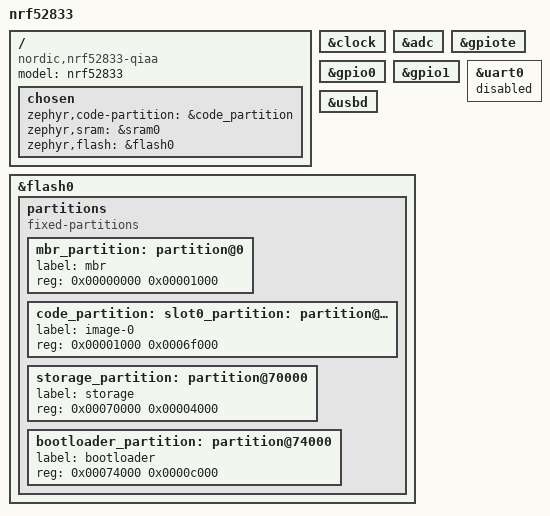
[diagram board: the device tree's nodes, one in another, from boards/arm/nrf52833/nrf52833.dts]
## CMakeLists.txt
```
cmake_minimum_required(VERSION 3.20.0)

set(NO_BUILD_TYPE_WARNING ON)
list(APPEND BOARD_ROOT ${CMAKE_CURRENT_SOURCE_DIR})

set(KBD_HEADER "${CMAKE_CURRENT_SOURCE_DIR}/keyboards/${KEYBOARD}/keyboard.h")

if(EXISTS ${KBD_HEADER})
  file(READ ${KBD_HEADER} _kbd_h)

  if(_kbd_h MATCHES "#define[ \t]+RGB[ \t]+true")
    string(REGEX MATCH "#define[ \t]+RGB_PORT[ \t]+([0-9]+)" _ "${_kbd_h}")
    set(RGB_PORT ${CMAKE_MATCH_1})
    string(REGEX MATCH "#define[ \t]+RGB_PIN[ \t]+([0-9]+)"  _ "${_kbd_h}")
    set(RGB_PIN  ${CMAKE_MATCH_1})
    string(REGEX MATCH "#define[ \t]+RGB_LEDS[ \t]+([0-9]+)" _ "${_kbd_h}")
    set(RGB_LEDS ${CMAKE_MATCH_1})

    if(RGB_PORT STREQUAL "" OR RGB_PIN STREQUAL "" OR RGB_LEDS STREQUAL "")
      message(FATAL_ERROR "RGB enabled for ${KEYBOARD} but RGB_PORT/RGB_PIN/RGB_LEDS not defined in keyboard.h")
    endif()

    message(STATUS "RGB enabled for ${KEYBOARD}: port=${RGB_PORT} pin=${RGB_PIN} leds=${RGB_LEDS}")
    list(APPEND EXTRA_CONF_FILE "boards/arm/common/rgb.conf")
    list(APPEND DTC_OVERLAY_FILE "boards/arm/common/rgb.overlay")
    list(APPEND DTS_EXTRA_CPPFLAGS
      "-DRGB_PORT=${RGB_PORT}"
      "-DRGB_PIN=${RGB_PIN}"
      "-DRGB_LEDS=${RGB_LEDS}")
  endif()

  if(_kbd_h MATCHES "#define[ \t]+LOGS[ \t]+true")
    list(APPEND EXTRA_CONF_FILE "boards/arm/common/logs.conf")
    list(APPEND DTC_OVERLAY_FILE "boards/arm/common/logs.overlay")
  endif()
endif()

list(APPEND DTC_OVERLAY_FILE "boards/arm/common/battery.overlay")

find_package(Zephyr REQUIRED HINTS $ENV{ZEPHYR_BASE})
project(keyboard-firmware)

if(NOT DEFINED KEYBOARD)
  message(FATAL_ERROR "KEYBOARD not defined. Example: -DKEYBOARD=miguelio/mk60v1")
endif()

target_include_directories(app PRIVATE src)
target_include_directories(app PRIVATE keyboards/${KEYBOARD})

target_sources(app PRIVATE
  keyboards/${KEYBOARD}/keyboard.c
  keyboards/${KEYBOARD}/keymap.c
  src/battery/battery.c
  src/main.c
)
```

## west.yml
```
manifest:
  remotes:
    - name: zephyrproject-rtos
      url-base: https://github.com/zephyrproject-rtos

  projects:
    - name: zephyr
      remote: zephyrproject-rtos
      revision: v3.6.0
      clone-depth: 1
      import:
        name-allowlist:
          - cmsis
          - hal_nordic
          - mbedtls
          - tinycrypt
          - segger

  self:
    path: app
```

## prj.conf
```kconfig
# General
CONFIG_LOG=y
CONFIG_PRINTK=y
CONFIG_REBOOT=y
CONFIG_MPU_STACK_GUARD=y

# Bluetooth
CONFIG_BT=y
CONFIG_BT_PERIPHERAL=y
CONFIG_BT_DEVICE_NAME="BMK Keyboard"
CONFIG_BT_DEVICE_APPEARANCE=961
CONFIG_BT_MAX_CONN=1
CONFIG_BT_MAX_PAIRED=1
CONFIG_BT_GATT_DYNAMIC_DB=y

# BLE Security - pairing support for HID
CONFIG_BT_SMP=y
CONFIG_BT_SMP_SC_ONLY=n
CONFIG_BT_SMP_SC_PAIR_ONLY=n
CONFIG_BT_SMP_ALLOW_UNAUTH_OVERWRITE=y

# BLE connection parameters for compatibility
CONFIG_BT_PERIPHERAL_PREF_MIN_INT=6
CONFIG_BT_PERIPHERAL_PREF_MAX_INT=9
CONFIG_BT_PERIPHERAL_PREF_LATENCY=150
CONFIG_BT_PERIPHERAL_PREF_TIMEOUT=400

# Security
CONFIG_BT_SMP=y
CONFIG_BT_ID_MAX=2
CONFIG_BT_KEYS_OVERWRITE_OLDEST=y

# Performance
CONFIG_BT_CTLR_TX_PWR_PLUS_8=y
CONFIG_BT_L2CAP_TX_BUF_COUNT=8

# Watchdog
CONFIG_WATCHDOG=y
CONFIG_WDT_DISABLE_AT_BOOT=y

# Device Information Service
CONFIG_BT_DIS=y
CONFIG_BT_DIS_PNP=y
CONFIG_BT_DIS_PNP_VID_SRC=2
CONFIG_BT_DIS_PNP_VID=0x1D50
CONFIG_BT_DIS_PNP_PID=0x615E
CONFIG_BT_DIS_PNP_VER=0x0001
CONFIG_BT_DIS_MODEL="BMK Keyboard"
CONFIG_BT_DIS_MANUF="BMK"

# Battery Service
CONFIG_BT_BAS=y
CONFIG_ADC=y

# Settings
CONFIG_SETTINGS=y
CONFIG_BT_SETTINGS=y
CONFIG_SETTINGS_DYNAMIC_HANDLERS=y

# USB HID
CONFIG_USB_DEVICE_STACK=y
CONFIG_USB_DEVICE_HID=y
CONFIG_USB_DEVICE_PRODUCT="BMK Keyboard"
CONFIG_USB_DEVICE_VID=0x1D50
CONFIG_USB_DEVICE_PID=0x615E
CONFIG_USB_DEVICE_INITIALIZE_AT_BOOT=y
```

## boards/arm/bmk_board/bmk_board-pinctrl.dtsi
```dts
/*
 * Copyright (c) 2025 Miguelio
 * SPDX-License-Identifier: MIT
 */

&pinctrl {
};
```

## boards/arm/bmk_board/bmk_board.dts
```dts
/*
 * Copyright (c) 2025 Miguelio
 * SPDX-License-Identifier: MIT
 *
 * Board: E73-2G4M08S1C (nRF52840)
 * - No external 32.768kHz crystal (uses internal RC)
 * - Powered via VDDH from USB (5V)
 */

/dts-v1/;
#include <nordic/nrf52840_qiaa.dtsi>

/ {
	model = "bmk_board";
	compatible = "bmk_board";

	chosen {
		zephyr,code-partition = &code_partition;
		zephyr,sram = &sram0;
		zephyr,flash = &flash0;
		zephyr,console = &uart0;
		zephyr,shell-uart = &uart0;
	};

};

&adc {
	status = "okay";
};

&gpiote {
	status = "okay";
};

&gpio0 {
	status = "okay";
};

&gpio1 {
	status = "okay";
};

&uart0 {
	status = "disabled";
};

zephyr_udc0: &usbd {
	status = "okay";
};

&flash0 {
	partitions {
		compatible = "fixed-partitions";
		#address-cells = <1>;
		#size-cells = <1>;

		sd_partition: partition@0 {
			reg = <0x00000000 0x00001000>;
		};

		code_partition: partition@1000 {
			reg = <0x00001000 0x000d3000>;
		};

		storage_partition: partition@d4000 {
			reg = <0x000d4000 0x00020000>;
		};

		boot_partition: partition@f4000 {
			reg = <0x000f4000 0x0000c000>;
		};
	};
};
```

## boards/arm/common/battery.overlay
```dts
/ {
    zephyr,user {
        io-channels = <&adc 0>;
    };
};

&adc {
    status = "okay";
    #address-cells = <1>;
    #size-cells = <0>;

    channel@0 {
        reg = <0>;
        zephyr,gain = "ADC_GAIN_1_2";
        zephyr,reference = "ADC_REF_INTERNAL";
        zephyr,acquisition-time = <ADC_ACQ_TIME(ADC_ACQ_TIME_MICROSECONDS, 20)>;
        zephyr,oversampling = <2>;
        zephyr,input-positive = <NRF_SAADC_VDDHDIV5>;
        zephyr,resolution = <12>;
    };
};
```

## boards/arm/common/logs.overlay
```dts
/ {
	chosen {
        zephyr,console = &cdc_acm_uart0;
		zephyr,shell-uart = &cdc_acm_uart0;
	};
};

zephyr_udc0: &usbd {
	status = "okay";

	cdc_acm_uart0: cdc_acm_uart0 {
		compatible = "zephyr,cdc-acm-uart";
	};
};
```

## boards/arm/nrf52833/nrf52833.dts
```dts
/*
 * Copyright (c) 2026 Miguelio
 * SPDX-License-Identifier: MIT
 *
 * Board: E73-2G4M08S1C (nRF52833)
 * - No external 32.768kHz crystal (uses internal RC)
 * - Powered via VDDH from USB (5V)
 */

/dts-v1/;
#include <nordic/nrf52833_qiaa.dtsi>

/ {
	model = "nrf52833";
	compatible = "nordic,nrf52833-qiaa";

	chosen {
		zephyr,code-partition = &code_partition;
		zephyr,sram = &sram0;
		zephyr,flash = &flash0;
	};
};

&clock {
	status = "okay";
};

&adc {
	status = "okay";
};

&gpiote {
	status = "okay";
};

&gpio0 {
	status = "okay";
};

&gpio1 {
	status = "okay";
};

&uart0 {
	status = "disabled";
};

zephyr_udc0: &usbd {
	status = "okay";
};

&flash0 {
    partitions {
        compatible = "fixed-partitions";
        #address-cells = <1>;
        #size-cells = <1>;

        mbr_partition: partition@0 {
            label = "mbr";
            reg = <0x00000000 0x00001000>;
        };

        code_partition: slot0_partition: partition@1000 {
            label = "image-0";
            reg = <0x00001000 0x0006f000>; /* Hasta la 0x70000 */
        };

        storage_partition: partition@70000 {
            label = "storage";
            reg = <0x00070000 0x00004000>; /* 16KB para datos */
        };

        bootloader_partition: partition@74000 {
            label = "bootloader";
            reg = <0x00074000 0x0000c000>; /* 48KB finales */
        };
    };
};
```

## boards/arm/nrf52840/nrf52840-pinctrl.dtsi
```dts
/*
 * Copyright (c) 2026 Miguelio
 * SPDX-License-Identifier: MIT
 */

&pinctrl {
};
```

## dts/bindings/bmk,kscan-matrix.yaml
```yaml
description: BMK keyboard scan matrix

compatible: "bmk,kscan-matrix"

properties:
  col-gpios:
    type: phandle-array
    required: true
    description: Column GPIO pins (active high output)

  row-gpios:
    type: phandle-array
    required: true
    description: Row GPIO pins (active high input with pull-down)
```

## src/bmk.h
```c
#ifndef BMK_H
#define BMK_H

#include <zephyr/types.h>
#include <stdint.h>
#include <stdbool.h>
#include <zephyr/kernel.h>
#include <zephyr/drivers/gpio.h>
#include <zephyr/bluetooth/bluetooth.h>
#include <zephyr/bluetooth/conn.h>
#include <zephyr/bluetooth/gatt.h>
#include <zephyr/bluetooth/uuid.h>
#include <zephyr/usb/usb_device.h>
#include <zephyr/usb/class/usb_hid.h>
#include <zephyr/pm/device.h>
#include <hal/nrf_power.h>
#include <zephyr/drivers/gpio.h>
#include <zephyr/device.h>
#include <zephyr/usb/class/usb_hid.h>
#include <zephyr/devicetree.h>
#include <zephyr/drivers/gpio.h>
#include <zephyr/logging/log.h>
#include <zephyr/drivers/led_strip.h>
#include <zephyr/bluetooth/services/bas.h>
#include <zephyr/settings/settings.h>
#include <zephyr/sys/reboot.h>
#include <hal/nrf_gpio.h>

#include "hid.h"

#define ENCODER_PINS 2

#define P0(pin) (0x0000 | (pin & 0xFF))
#define P1(pin) (0x0100 | (pin & 0xFF))

extern const uint16_t pin_cols[];
extern const uint16_t pin_rows[];
extern const uint16_t pin_encoders[ENCODER_PINS];
extern const uint16_t pin_power_ext;

#define GPIO0 DEVICE_DT_GET(DT_NODELABEL(gpio0))
#define GPIO1 DEVICE_DT_GET(DT_NODELABEL(gpio1))

#endif
```

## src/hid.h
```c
#pragma once

#include <zephyr/sys/util.h>

#include <zephyr/usb/usb_device.h>
#include <zephyr/usb/class/usb_hid.h>

#define K_KEYBOARD 0x0000
#define K_CONSUMER 0x1000
#define K_FN 0x2000
#define K_SPECIAL 0x3000
#define K_TAP_HOLD 0xE000

#define HID_KEY_LCTRL (K_KEYBOARD | 0xE0)
#define HID_KEY_LSHIFT (K_KEYBOARD | 0xE1)
#define HID_KEY_LALT (K_KEYBOARD | 0xE2)
#define HID_KEY_LGUI (K_KEYBOARD | 0xE3)
#define HID_KEY_RCTRL (K_KEYBOARD | 0xE4)
#define HID_KEY_RSHIFT (K_KEYBOARD | 0xE5)
#define HID_KEY_RALT (K_KEYBOARD | 0xE6)
#define HID_KEY_RGUI (K_KEYBOARD | 0xE7)

#define HID_KEY_NONE 0
#define HID_KEY_NUBS 0x64
#define HID_KEY_VOLUME_UP (K_CONSUMER | 0xE9)
#define HID_KEY_VOLUME_DOWN (K_CONSUMER | 0xEA)
#define HID_KEY_MUTE (K_CONSUMER | 0xE2)
#define HID_KEY_PLAY_PAUSE (K_CONSUMER | 0xCD)
#define HID_KEY_NEXT_TRACK (K_CONSUMER | 0xB5)
#define HID_KEY_PREV_TRACK (K_CONSUMER | 0xB6)
#define HID_KEY_STOP (K_CONSUMER | 0xB7)
#define HID_KEY_EJECT (K_CONSUMER | 0xB8)
#define HID_KEY_SLEEP (K_CONSUMER | 0x32)

#define HID_KEY_TRANS (K_SPECIAL | 0x01)

#define HID_KEY_POWER_ON (K_SPECIAL | 0x02)
#define HID_KEY_POWER_OFF (K_SPECIAL | 0x03)

#define HID_KEY_RGB_LIGHT (K_SPECIAL | 0x04)
#define HID_KEY_RGB_COLOR (K_SPECIAL | 0x05)
#define HID_KEY_RGB_SATURATION (K_SPECIAL | 0x06)
#define HID_KEY_RGB_ON (K_SPECIAL | 0x07)
#define HID_KEY_RGB_OFF (K_SPECIAL | 0x08)
#define HID_KEY_RGB_TOGGLE (K_SPECIAL | 0x09)

#define HID_BT_CLEAR (K_SPECIAL | 0x0A)
#define HID_DEEP_SLEEP (K_SPECIAL | 0x0B)
#define HID_RESET (K_SPECIAL | 0x0C)
#define HID_BOOT (K_SPECIAL | 0x0D)

#define BMK_HID_REPORT_ID_KEYBOARD 0x01
#define BMK_HID_REPORT_ID_CONSUMER 0x02
#define BMK_HID_REPORT_ID_LEDS 0x01

#define HID_USAGE_GD_KEYBOARD (0x06)
#define HID_USAGE_KEY (0x07)
#define HID_USAGE_LED (0x08)
#define HID_USAGE_CONSUMER (0x0C)
#define HID_USAGE_KEY_KEYBOARD_LEFTCONTROL (0xE0)
#define HID_USAGE_KEY_KEYBOARD_RIGHT_GUI (0xE7)
#define HID_USAGE_LED_NUM_LOCK (0x01)
#define HID_USAGE_LED_KANA (0x05)
#define HID_USAGE_CONSUMER_CONSUMER_CONTROL (0x01)

#define FN_MO(layer) (0x2100 | (layer & 0xFF))
#define FN_TO(layer) (0x2200 | (layer & 0xFF))
#define TH_LCTRL(key) (0xE000 | (key & 0xFF))
#define TH_LSHIFT(key) (0xE100 | (key & 0xFF))
#define TH_LALT(key) (0xE200 | (key & 0xFF))
#define TH_LGUI(key) (0xE300 | (key & 0xFF))
#define TH_RCTRL(key) (0xE400 | (key & 0xFF))
#define TH_RSHIFT(key) (0xE500 | (key & 0xFF))
#define TH_RALT(key) (0xE600 | (key & 0xFF))
#define TH_RGUI(key) (0xE700 | (key & 0xFF))

#define BMK_HID_MAIN_VAL_DATA (0x00 << 0)
#define BMK_HID_MAIN_VAL_VAR (0x01 << 1)
#define BMK_HID_MAIN_VAL_ABS (0x00 << 2)
#define BMK_HID_MAIN_VAL_CONST (0x01 << 0)
#define BMK_HID_MAIN_VAL_ARRAY (0x00 << 1)

static const uint8_t hid_report_map[] = {
    HID_USAGE_PAGE(HID_USAGE_GEN_DESKTOP),
    HID_USAGE(HID_USAGE_GD_KEYBOARD),
    HID_COLLECTION(HID_COLLECTION_APPLICATION),
    HID_REPORT_ID(BMK_HID_REPORT_ID_KEYBOARD),
    HID_USAGE_PAGE(HID_USAGE_KEY),
    HID_USAGE_MIN8(HID_USAGE_KEY_KEYBOARD_LEFTCONTROL),
    HID_USAGE_MAX8(HID_USAGE_KEY_KEYBOARD_RIGHT_GUI),
    HID_LOGICAL_MIN8(0x00),
    HID_LOGICAL_MAX8(0x01),

    HID_REPORT_SIZE(0x01),
    HID_REPORT_COUNT(0x08),
    HID_INPUT(BMK_HID_MAIN_VAL_DATA | BMK_HID_MAIN_VAL_VAR | BMK_HID_MAIN_VAL_ABS),

    HID_USAGE_PAGE(HID_USAGE_KEY),
    HID_REPORT_SIZE(0x08),
    HID_REPORT_COUNT(0x01),
    HID_INPUT(BMK_HID_MAIN_VAL_CONST | BMK_HID_MAIN_VAL_VAR | BMK_HID_MAIN_VAL_ABS),

    HID_USAGE_PAGE(HID_USAGE_LED),
    HID_USAGE_MIN8(HID_USAGE_LED_NUM_LOCK),
    HID_USAGE_MAX8(HID_USAGE_LED_KANA),
    HID_REPORT_SIZE(0x01),
    HID_REPORT_COUNT(0x05),
    HID_OUTPUT(BMK_HID_MAIN_VAL_DATA | BMK_HID_MAIN_VAL_VAR | BMK_HID_MAIN_VAL_ABS),

    HID_USAGE_PAGE(HID_USAGE_LED),
    HID_REPORT_SIZE(0x03),
    HID_REPORT_COUNT(0x01),
    HID_OUTPUT(BMK_HID_MAIN_VAL_CONST | BMK_HID_MAIN_VAL_VAR | BMK_HID_MAIN_VAL_ABS),

    HID_USAGE_PAGE(HID_USAGE_KEY),

    HID_LOGICAL_MIN8(0x00),
    HID_LOGICAL_MAX16(0xFF, 0x00),
    HID_USAGE_MIN8(0x00),
    HID_USAGE_MAX8(0xFF),
    HID_REPORT_SIZE(0x08),
    HID_REPORT_COUNT(0x06),
    HID_INPUT(BMK_HID_MAIN_VAL_DATA | BMK_HID_MAIN_VAL_ARRAY | BMK_HID_MAIN_VAL_ABS),

    HID_END_COLLECTION,

    HID_USAGE_PAGE(HID_USAGE_CONSUMER),
    HID_USAGE(HID_USAGE_CONSUMER_CONSUMER_CONTROL),
    HID_COLLECTION(HID_COLLECTION_APPLICATION),
    HID_REPORT_ID(BMK_HID_REPORT_ID_CONSUMER),
    HID_USAGE_PAGE(HID_USAGE_CONSUMER),

    HID_LOGICAL_MIN8(0x00),
    HID_LOGICAL_MAX16(0xFF, 0x00),
    HID_USAGE_MIN8(0x00),
    HID_USAGE_MAX8(0xFF),
    HID_REPORT_SIZE(0x08),
    HID_REPORT_COUNT(0x06),
    HID_INPUT(BMK_HID_MAIN_VAL_DATA | BMK_HID_MAIN_VAL_ARRAY | BMK_HID_MAIN_VAL_ABS),
    HID_END_COLLECTION,
};
```

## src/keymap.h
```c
#ifndef KEYMAP_H
#define KEYMAP_H

#include "matrix.h"

#define LAYERS 2

#define HID_KEY_NUBS 0x64
#define HID_KEY_NONE 0

struct key {
    uint8_t kc[LAYERS];
    bool pressed;
    uint8_t debounce_count;
};

extern const uint8_t layers[LAYERS][MATRIX_COLS * MATRIX_ROWS];

#endif
```

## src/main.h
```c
#ifndef MAIN_H
#define MAIN_H

#include "keyboard.h"
#include "battery/battery.h"

// Static variables
#define SEND_THREAD_STACK_SIZE 1024
#define SEND_THREAD_PRIORITY 7
#define SEND_THREAD_CACHE_SIZE 16
#define CYCLE_BASE_DELAY 1000

// Config parameters
#ifndef DEBOUNCE_PRESS
#define DEBOUNCE_PRESS 5
#endif
#ifndef DEBOUNCE_RELEASE
#define DEBOUNCE_RELEASE 15
#endif
#ifndef DEBOUNCE_ENCODER
#define DEBOUNCE_ENCODER 5
#endif
#ifndef CYCLE_DELAY
#define CYCLE_DELAY CYCLE_BASE_DELAY
#endif
#ifndef SLEEP_TIMEOUT_ADV
#define SLEEP_TIMEOUT_ADV 300
#endif
#ifndef SLEEP_TIMEOUT
#define SLEEP_TIMEOUT 10
#endif
#ifndef DEEP_SLEEP_TIMEOUT
#define DEEP_SLEEP_TIMEOUT 30
#endif
#define SLEEP_TIMEOUT_MS (SLEEP_TIMEOUT * CYCLE_BASE_DELAY)
#define SLEEP_TIMEOUT_ADV_MS (SLEEP_TIMEOUT_ADV * CYCLE_BASE_DELAY)
#ifndef TAP_HOLD_PRESS_DELAY
#define TAP_HOLD_PRESS_DELAY 175
#endif
#ifndef TAP_HOLD_RELEASE_DELAY
#define TAP_HOLD_RELEASE_DELAY 150
#endif
#ifndef TAP_HOLD_SIZE_ARRAY
#define TAP_HOLD_SIZE_ARRAY 3
#endif
#ifndef LOG_LEVEL
#define LOG_LEVEL LOG_LEVEL_DBG
#endif
#ifndef ENCODERS
#define ENCODERS 0
#endif
#ifndef USB
#define USB true
#endif
#ifndef USB_CHECK_TIMEOUT
#define USB_CHECK_TIMEOUT 1000
#endif

#ifndef RGB
#define RGB false
#endif
#ifndef RGB_COLOR_JUMP
#define RGB_COLOR_JUMP 5
#endif
#ifndef RGB_LIGHT_JUMP
#define RGB_LIGHT_JUMP 32
#endif
#ifndef RGB_SATURATION_JUMP
#define RGB_SATURATION_JUMP 32
#endif
#ifndef RGB_ON_STARTUP
#define RGB_ON_STARTUP true
#endif
#ifndef RGB_ON_STARTUP
#define RGB_ON_STARTUP true
#endif
#ifndef RGB_EFFECTS
#define RGB_EFFECTS RGB
#endif
#ifndef RGB_EFF_RAINBOW
#define RGB_EFF_RAINBOW RGB_EFFECTS
#endif
#ifndef RGB_EFF_COLORS
#define RGB_EFF_COLORS RGB_EFFECTS
#endif
#ifndef RGB_EFF_KITT
#define RGB_EFF_KITT RGB_EFFECTS
#endif

#ifndef POWER_EXT
#define POWER_EXT false
#endif
#ifndef POWER_EXT_RGB_LINKED
#define POWER_EXT_RGB_LINKED true
#endif
#ifndef POWER_EXT_RGB_DELAY
#define POWER_EXT_RGB_DELAY 5
#endif
#ifndef POWER_EXT_ON
#define POWER_EXT_ON true
#endif

#ifndef BATTERY
#define BATTERY true
#endif

#ifndef LOGS
#define LOGS false
#endif

struct key
{
    uint16_t kc[LAYERS];
    bool pressed;
    bool tapped;
    bool held;
    uint8_t debounce_count;
    uint8_t delay_press_count;
    uint8_t delay_release_count;
};

struct encoder_key
{
    uint16_t left_kc[LAYERS];
    uint16_t right_kc[LAYERS];
    uint8_t last_value;
    uint8_t debounce_count;
    int direction;
};

typedef enum
{
    BMK_KEYBOARD = BMK_HID_REPORT_ID_KEYBOARD,
    BMK_CONSUMER = BMK_HID_REPORT_ID_CONSUMER
} bmk_report_type_t;

typedef struct
{
    bmk_report_type_t type;
    uint8_t report[9];
    uint8_t report_consumer[7];
} thread_report_t;

typedef struct
{
    uint8_t idx;
    uint8_t layer;
} held_mod_key_t;

struct timeout_tapped_keys
{
    struct k_work_delayable dwork;
    uint8_t key_idx;
};

#endif
```

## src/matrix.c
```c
#include <zephyr/device.h>
#include <zephyr/devicetree.h>
#include <zephyr/drivers/gpio.h>
#include <zephyr/logging/log.h>

#include "matrix.h"

LOG_MODULE_DECLARE(bmk, LOG_LEVEL_INF);

#define GPIO0 DEVICE_DT_GET(DT_NODELABEL(gpio0))
#define GPIO1 DEVICE_DT_GET(DT_NODELABEL(gpio1))

const struct gpio_dt_spec cols[MATRIX_COLS] = {
	{ .port = GPIO0, .pin = 28, .dt_flags = GPIO_ACTIVE_HIGH },  /* Col 0: P0.28 */
	{ .port = GPIO0, .pin = 22, .dt_flags = GPIO_ACTIVE_HIGH },  /* Col 1: P0.22 */
	{ .port = GPIO0, .pin = 31, .dt_flags = GPIO_ACTIVE_HIGH },  /* Col 2: P0.31 */
	{ .port = GPIO0, .pin = 29, .dt_flags = GPIO_ACTIVE_HIGH },  /* Col 3: P0.29 */
	{ .port = GPIO0, .pin =  2, .dt_flags = GPIO_ACTIVE_HIGH },  /* Col 4: P0.02 */
	{ .port = GPIO1, .pin = 13, .dt_flags = GPIO_ACTIVE_HIGH },  /* Col 5: P1.13 */
	{ .port = GPIO0, .pin =  3, .dt_flags = GPIO_ACTIVE_HIGH },  /* Col 6: P0.03 */
	{ .port = GPIO1, .pin = 11, .dt_flags = GPIO_ACTIVE_HIGH },  /* Col 7: P1.11 */
};

const struct gpio_dt_spec rows[MATRIX_ROWS] = {
	{ .port = GPIO0, .pin = 13, .dt_flags = GPIO_ACTIVE_HIGH },  /* Row 0: P0.13 */
	{ .port = GPIO0, .pin = 24, .dt_flags = GPIO_ACTIVE_HIGH },  /* Row 1: P0.24 */
	{ .port = GPIO0, .pin = 10, .dt_flags = GPIO_ACTIVE_HIGH },  /* Row 2: P0.10 */
	{ .port = GPIO0, .pin =  4, .dt_flags = GPIO_ACTIVE_HIGH },  /* Row 3: P0.04 */
	{ .port = GPIO0, .pin = 12, .dt_flags = GPIO_ACTIVE_HIGH },  /* Row 4: P0.12 */
	{ .port = GPIO0, .pin =  7, .dt_flags = GPIO_ACTIVE_HIGH },  /* Row 5: P0.07 */
	{ .port = GPIO1, .pin =  2, .dt_flags = GPIO_ACTIVE_HIGH },  /* Row 6: P1.02 */
	{ .port = GPIO1, .pin =  4, .dt_flags = GPIO_ACTIVE_HIGH },  /* Row 7: P1.04 */
	{ .port = GPIO1, .pin =  6, .dt_flags = GPIO_ACTIVE_HIGH },  /* Row 8: P1.06 */
};
```

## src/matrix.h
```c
#ifndef MATRIX_H
#define MATRIX_H

#include <stdint.h>
#include <stdbool.h>
#include <zephyr/drivers/gpio.h>

#define MATRIX_COLS 8
#define MATRIX_ROWS 9

#define DEBOUNCE_PRESS 5
#define DEBOUNCE_RELEASE 20

extern const struct gpio_dt_spec cols[MATRIX_COLS];
extern const struct gpio_dt_spec rows[MATRIX_ROWS];

#endif
```

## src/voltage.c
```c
#include <hal/nrf_uicr.h>
#include <hal/nrf_nvmc.h>
#include <cmsis_core.h>

static int set_vdd_3v(void)
{
    uint32_t regout0 =
        (UICR_REGOUT0_VOUT_3V0 << UICR_REGOUT0_VOUT_Pos);

    if ((NRF_UICR->REGOUT0 & UICR_REGOUT0_VOUT_Msk) != regout0) {

        NRF_NVMC->CONFIG = NVMC_CONFIG_WEN_Wen;
        while (NRF_NVMC->READY == NVMC_READY_READY_Busy);

        NRF_UICR->REGOUT0 = regout0;

        while (NRF_NVMC->READY == NVMC_READY_READY_Busy);

        NRF_NVMC->CONFIG = NVMC_CONFIG_WEN_Ren;

        NVIC_SystemReset();
    }

    return 0;
}

SYS_INIT(set_vdd_3v, PRE_KERNEL_1, 0);
```
